VERSION 5.7 ;
BUSBITCHARS "[]" ;
DIVIDERCHAR "/" ;

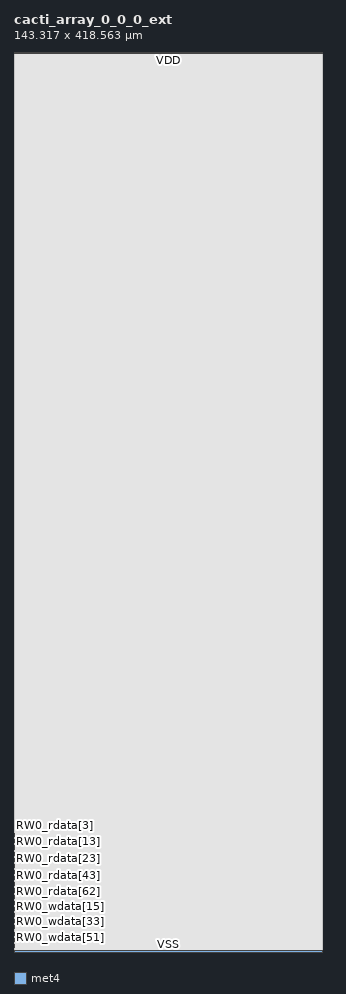
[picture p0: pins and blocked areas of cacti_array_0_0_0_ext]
MACRO cacti_array_0_0_0_ext
  CLASS BLOCK BLACKBOX ;
  ORIGIN 0 0 ;
  FOREIGN cacti_array_0_0_0_ext 0 0 ;
  SIZE 143.317 BY 418.563 ;
  SYMMETRY X Y ;

  PIN VDD
    DIRECTION INOUT ;
    USE POWER ;
    PORT
      LAYER met4 ;
        RECT 0.000 418.063 143.317 418.563 ;
    END
  END VDD
  PIN VSS
    DIRECTION INOUT ;
    USE GROUND ;
    PORT
      LAYER met4 ;
        RECT 0.000 0.000 143.317 0.500 ;
    END
  END VSS
  PIN RW0_clk
    DIRECTION INPUT ;
    USE CLOCK ;
    PORT
      LAYER met4 ;
        RECT 0.000 0.700 0.200 0.900 ;
    END
  END RW0_clk
  PIN RW0_en
    DIRECTION INPUT ;
    USE SIGNAL ;
    PORT
      LAYER met4 ;
        RECT 0.000 1.100 0.200 1.300 ;
    END
  END RW0_en
  PIN RW0_wmode
    DIRECTION INPUT ;
    USE SIGNAL ;
    PORT
      LAYER met4 ;
        RECT 0.000 1.500 0.200 1.700 ;
    END
  END RW0_wmode
  PIN RW0_addr[8]
    DIRECTION INPUT ;
    USE SIGNAL ;
    PORT
      LAYER met4 ;
        RECT 0.000 1.900 0.200 2.100 ;
    END
  END RW0_addr[8]
  PIN RW0_addr[7]
    DIRECTION INPUT ;
    USE SIGNAL ;
    PORT
      LAYER met4 ;
        RECT 0.000 2.300 0.200 2.500 ;
    END
  END RW0_addr[7]
  PIN RW0_addr[6]
    DIRECTION INPUT ;
    USE SIGNAL ;
    PORT
      LAYER met4 ;
        RECT 0.000 2.700 0.200 2.900 ;
    END
  END RW0_addr[6]
  PIN RW0_addr[5]
    DIRECTION INPUT ;
    USE SIGNAL ;
    PORT
      LAYER met4 ;
        RECT 0.000 3.100 0.200 3.300 ;
    END
  END RW0_addr[5]
  PIN RW0_addr[4]
    DIRECTION INPUT ;
    USE SIGNAL ;
    PORT
      LAYER met4 ;
        RECT 0.000 3.500 0.200 3.700 ;
    END
  END RW0_addr[4]
  PIN RW0_addr[3]
    DIRECTION INPUT ;
    USE SIGNAL ;
    PORT
      LAYER met4 ;
        RECT 0.000 3.900 0.200 4.100 ;
    END
  END RW0_addr[3]
  PIN RW0_addr[2]
    DIRECTION INPUT ;
    USE SIGNAL ;
    PORT
      LAYER met4 ;
        RECT 0.000 4.300 0.200 4.500 ;
    END
  END RW0_addr[2]
  PIN RW0_addr[1]
    DIRECTION INPUT ;
    USE SIGNAL ;
    PORT
      LAYER met4 ;
        RECT 0.000 4.700 0.200 4.900 ;
    END
  END RW0_addr[1]
  PIN RW0_addr[0]
    DIRECTION INPUT ;
    USE SIGNAL ;
    PORT
      LAYER met4 ;
        RECT 0.000 5.100 0.200 5.300 ;
    END
  END RW0_addr[0]
  PIN RW0_wdata[63]
    DIRECTION INPUT ;
    USE SIGNAL ;
    PORT
      LAYER met4 ;
        RECT 0.000 5.500 0.200 5.700 ;
    END
  END RW0_wdata[63]
  PIN RW0_wdata[62]
    DIRECTION INPUT ;
    USE SIGNAL ;
    PORT
      LAYER met4 ;
        RECT 0.000 5.900 0.200 6.100 ;
    END
  END RW0_wdata[62]
  PIN RW0_wdata[61]
    DIRECTION INPUT ;
    USE SIGNAL ;
    PORT
      LAYER met4 ;
        RECT 0.000 6.300 0.200 6.500 ;
    END
  END RW0_wdata[61]
  PIN RW0_wdata[60]
    DIRECTION INPUT ;
    USE SIGNAL ;
    PORT
      LAYER met4 ;
        RECT 0.000 6.700 0.200 6.900 ;
    END
  END RW0_wdata[60]
  PIN RW0_wdata[59]
    DIRECTION INPUT ;
    USE SIGNAL ;
    PORT
      LAYER met4 ;
        RECT 0.000 7.100 0.200 7.300 ;
    END
  END RW0_wdata[59]
  PIN RW0_wdata[58]
    DIRECTION INPUT ;
    USE SIGNAL ;
    PORT
      LAYER met4 ;
        RECT 0.000 7.500 0.200 7.700 ;
    END
  END RW0_wdata[58]
  PIN RW0_wdata[57]
    DIRECTION INPUT ;
    USE SIGNAL ;
    PORT
      LAYER met4 ;
        RECT 0.000 7.900 0.200 8.100 ;
    END
  END RW0_wdata[57]
  PIN RW0_wdata[56]
    DIRECTION INPUT ;
    USE SIGNAL ;
    PORT
      LAYER met4 ;
        RECT 0.000 8.300 0.200 8.500 ;
    END
  END RW0_wdata[56]
  PIN RW0_wdata[55]
    DIRECTION INPUT ;
    USE SIGNAL ;
    PORT
      LAYER met4 ;
        RECT 0.000 8.700 0.200 8.900 ;
    END
  END RW0_wdata[55]
  PIN RW0_wdata[54]
    DIRECTION INPUT ;
    USE SIGNAL ;
    PORT
      LAYER met4 ;
        RECT 0.000 9.100 0.200 9.300 ;
    END
  END RW0_wdata[54]
  PIN RW0_wdata[53]
    DIRECTION INPUT ;
    USE SIGNAL ;
    PORT
      LAYER met4 ;
        RECT 0.000 9.500 0.200 9.700 ;
    END
  END RW0_wdata[53]
  PIN RW0_wdata[52]
    DIRECTION INPUT ;
    USE SIGNAL ;
    PORT
      LAYER met4 ;
        RECT 0.000 9.900 0.200 10.100 ;
    END
  END RW0_wdata[52]
  PIN RW0_wdata[51]
    DIRECTION INPUT ;
    USE SIGNAL ;
    PORT
      LAYER met4 ;
        RECT 0.000 10.300 0.200 10.500 ;
    END
  END RW0_wdata[51]
  PIN RW0_wdata[50]
    DIRECTION INPUT ;
    USE SIGNAL ;
    PORT
      LAYER met4 ;
        RECT 0.000 10.700 0.200 10.900 ;
    END
  END RW0_wdata[50]
  PIN RW0_wdata[49]
    DIRECTION INPUT ;
    USE SIGNAL ;
    PORT
      LAYER met4 ;
        RECT 0.000 11.100 0.200 11.300 ;
    END
  END RW0_wdata[49]
  PIN RW0_wdata[48]
    DIRECTION INPUT ;
    USE SIGNAL ;
    PORT
      LAYER met4 ;
        RECT 0.000 11.500 0.200 11.700 ;
    END
  END RW0_wdata[48]
  PIN RW0_wdata[47]
    DIRECTION INPUT ;
    USE SIGNAL ;
    PORT
      LAYER met4 ;
        RECT 0.000 11.900 0.200 12.100 ;
    END
  END RW0_wdata[47]
  PIN RW0_wdata[46]
    DIRECTION INPUT ;
    USE SIGNAL ;
    PORT
      LAYER met4 ;
        RECT 0.000 12.300 0.200 12.500 ;
    END
  END RW0_wdata[46]
  PIN RW0_wdata[45]
    DIRECTION INPUT ;
    USE SIGNAL ;
    PORT
      LAYER met4 ;
        RECT 0.000 12.700 0.200 12.900 ;
    END
  END RW0_wdata[45]
  PIN RW0_wdata[44]
    DIRECTION INPUT ;
    USE SIGNAL ;
    PORT
      LAYER met4 ;
        RECT 0.000 13.100 0.200 13.300 ;
    END
  END RW0_wdata[44]
  PIN RW0_wdata[43]
    DIRECTION INPUT ;
    USE SIGNAL ;
    PORT
      LAYER met4 ;
        RECT 0.000 13.500 0.200 13.700 ;
    END
  END RW0_wdata[43]
  PIN RW0_wdata[42]
    DIRECTION INPUT ;
    USE SIGNAL ;
    PORT
      LAYER met4 ;
        RECT 0.000 13.900 0.200 14.100 ;
    END
  END RW0_wdata[42]
  PIN RW0_wdata[41]
    DIRECTION INPUT ;
    USE SIGNAL ;
    PORT
      LAYER met4 ;
        RECT 0.000 14.300 0.200 14.500 ;
    END
  END RW0_wdata[41]
  PIN RW0_wdata[40]
    DIRECTION INPUT ;
    USE SIGNAL ;
    PORT
      LAYER met4 ;
        RECT 0.000 14.700 0.200 14.900 ;
    END
  END RW0_wdata[40]
  PIN RW0_wdata[39]
    DIRECTION INPUT ;
    USE SIGNAL ;
    PORT
      LAYER met4 ;
        RECT 0.000 15.100 0.200 15.300 ;
    END
  END RW0_wdata[39]
  PIN RW0_wdata[38]
    DIRECTION INPUT ;
    USE SIGNAL ;
    PORT
      LAYER met4 ;
        RECT 0.000 15.500 0.200 15.700 ;
    END
  END RW0_wdata[38]
  PIN RW0_wdata[37]
    DIRECTION INPUT ;
    USE SIGNAL ;
    PORT
      LAYER met4 ;
        RECT 0.000 15.900 0.200 16.100 ;
    END
  END RW0_wdata[37]
  PIN RW0_wdata[36]
    DIRECTION INPUT ;
    USE SIGNAL ;
    PORT
      LAYER met4 ;
        RECT 0.000 16.300 0.200 16.500 ;
    END
  END RW0_wdata[36]
  PIN RW0_wdata[35]
    DIRECTION INPUT ;
    USE SIGNAL ;
    PORT
      LAYER met4 ;
        RECT 0.000 16.700 0.200 16.900 ;
    END
  END RW0_wdata[35]
  PIN RW0_wdata[34]
    DIRECTION INPUT ;
    USE SIGNAL ;
    PORT
      LAYER met4 ;
        RECT 0.000 17.100 0.200 17.300 ;
    END
  END RW0_wdata[34]
  PIN RW0_wdata[33]
    DIRECTION INPUT ;
    USE SIGNAL ;
    PORT
      LAYER met4 ;
        RECT 0.000 17.500 0.200 17.700 ;
    END
  END RW0_wdata[33]
  PIN RW0_wdata[32]
    DIRECTION INPUT ;
    USE SIGNAL ;
    PORT
      LAYER met4 ;
        RECT 0.000 17.900 0.200 18.100 ;
    END
  END RW0_wdata[32]
  PIN RW0_wdata[31]
    DIRECTION INPUT ;
    USE SIGNAL ;
    PORT
      LAYER met4 ;
        RECT 0.000 18.300 0.200 18.500 ;
    END
  END RW0_wdata[31]
  PIN RW0_wdata[30]
    DIRECTION INPUT ;
    USE SIGNAL ;
    PORT
      LAYER met4 ;
        RECT 0.000 18.700 0.200 18.900 ;
    END
  END RW0_wdata[30]
  PIN RW0_wdata[29]
    DIRECTION INPUT ;
    USE SIGNAL ;
    PORT
      LAYER met4 ;
        RECT 0.000 19.100 0.200 19.300 ;
    END
  END RW0_wdata[29]
  PIN RW0_wdata[28]
    DIRECTION INPUT ;
    USE SIGNAL ;
    PORT
      LAYER met4 ;
        RECT 0.000 19.500 0.200 19.700 ;
    END
  END RW0_wdata[28]
  PIN RW0_wdata[27]
    DIRECTION INPUT ;
    USE SIGNAL ;
    PORT
      LAYER met4 ;
        RECT 0.000 19.900 0.200 20.100 ;
    END
  END RW0_wdata[27]
  PIN RW0_wdata[26]
    DIRECTION INPUT ;
    USE SIGNAL ;
    PORT
      LAYER met4 ;
        RECT 0.000 20.300 0.200 20.500 ;
    END
  END RW0_wdata[26]
  PIN RW0_wdata[25]
    DIRECTION INPUT ;
    USE SIGNAL ;
    PORT
      LAYER met4 ;
        RECT 0.000 20.700 0.200 20.900 ;
    END
  END RW0_wdata[25]
  PIN RW0_wdata[24]
    DIRECTION INPUT ;
    USE SIGNAL ;
    PORT
      LAYER met4 ;
        RECT 0.000 21.100 0.200 21.300 ;
    END
  END RW0_wdata[24]
  PIN RW0_wdata[23]
    DIRECTION INPUT ;
    USE SIGNAL ;
    PORT
      LAYER met4 ;
        RECT 0.000 21.500 0.200 21.700 ;
    END
  END RW0_wdata[23]
  PIN RW0_wdata[22]
    DIRECTION INPUT ;
    USE SIGNAL ;
    PORT
      LAYER met4 ;
        RECT 0.000 21.900 0.200 22.100 ;
    END
  END RW0_wdata[22]
  PIN RW0_wdata[21]
    DIRECTION INPUT ;
    USE SIGNAL ;
    PORT
      LAYER met4 ;
        RECT 0.000 22.300 0.200 22.500 ;
    END
  END RW0_wdata[21]
  PIN RW0_wdata[20]
    DIRECTION INPUT ;
    USE SIGNAL ;
    PORT
      LAYER met4 ;
        RECT 0.000 22.700 0.200 22.900 ;
    END
  END RW0_wdata[20]
  PIN RW0_wdata[19]
    DIRECTION INPUT ;
    USE SIGNAL ;
    PORT
      LAYER met4 ;
        RECT 0.000 23.100 0.200 23.300 ;
    END
  END RW0_wdata[19]
  PIN RW0_wdata[18]
    DIRECTION INPUT ;
    USE SIGNAL ;
    PORT
      LAYER met4 ;
        RECT 0.000 23.500 0.200 23.700 ;
    END
  END RW0_wdata[18]
  PIN RW0_wdata[17]
    DIRECTION INPUT ;
    USE SIGNAL ;
    PORT
      LAYER met4 ;
        RECT 0.000 23.900 0.200 24.100 ;
    END
  END RW0_wdata[17]
  PIN RW0_wdata[16]
    DIRECTION INPUT ;
    USE SIGNAL ;
    PORT
      LAYER met4 ;
        RECT 0.000 24.300 0.200 24.500 ;
    END
  END RW0_wdata[16]
  PIN RW0_wdata[15]
    DIRECTION INPUT ;
    USE SIGNAL ;
    PORT
      LAYER met4 ;
        RECT 0.000 24.700 0.200 24.900 ;
    END
  END RW0_wdata[15]
  PIN RW0_wdata[14]
    DIRECTION INPUT ;
    USE SIGNAL ;
    PORT
      LAYER met4 ;
        RECT 0.000 25.100 0.200 25.300 ;
    END
  END RW0_wdata[14]
  PIN RW0_wdata[13]
    DIRECTION INPUT ;
    USE SIGNAL ;
    PORT
      LAYER met4 ;
        RECT 0.000 25.500 0.200 25.700 ;
    END
  END RW0_wdata[13]
  PIN RW0_wdata[12]
    DIRECTION INPUT ;
    USE SIGNAL ;
    PORT
      LAYER met4 ;
        RECT 0.000 25.900 0.200 26.100 ;
    END
  END RW0_wdata[12]
  PIN RW0_wdata[11]
    DIRECTION INPUT ;
    USE SIGNAL ;
    PORT
      LAYER met4 ;
        RECT 0.000 26.300 0.200 26.500 ;
    END
  END RW0_wdata[11]
  PIN RW0_wdata[10]
    DIRECTION INPUT ;
    USE SIGNAL ;
    PORT
      LAYER met4 ;
        RECT 0.000 26.700 0.200 26.900 ;
    END
  END RW0_wdata[10]
  PIN RW0_wdata[9]
    DIRECTION INPUT ;
    USE SIGNAL ;
    PORT
      LAYER met4 ;
        RECT 0.000 27.100 0.200 27.300 ;
    END
  END RW0_wdata[9]
  PIN RW0_wdata[8]
    DIRECTION INPUT ;
    USE SIGNAL ;
    PORT
      LAYER met4 ;
        RECT 0.000 27.500 0.200 27.700 ;
    END
  END RW0_wdata[8]
  PIN RW0_wdata[7]
    DIRECTION INPUT ;
    USE SIGNAL ;
    PORT
      LAYER met4 ;
        RECT 0.000 27.900 0.200 28.100 ;
    END
  END RW0_wdata[7]
  PIN RW0_wdata[6]
    DIRECTION INPUT ;
    USE SIGNAL ;
    PORT
      LAYER met4 ;
        RECT 0.000 28.300 0.200 28.500 ;
    END
  END RW0_wdata[6]
  PIN RW0_wdata[5]
    DIRECTION INPUT ;
    USE SIGNAL ;
    PORT
      LAYER met4 ;
        RECT 0.000 28.700 0.200 28.900 ;
    END
  END RW0_wdata[5]
  PIN RW0_wdata[4]
    DIRECTION INPUT ;
    USE SIGNAL ;
    PORT
      LAYER met4 ;
        RECT 0.000 29.100 0.200 29.300 ;
    END
  END RW0_wdata[4]
  PIN RW0_wdata[3]
    DIRECTION INPUT ;
    USE SIGNAL ;
    PORT
      LAYER met4 ;
        RECT 0.000 29.500 0.200 29.700 ;
    END
  END RW0_wdata[3]
  PIN RW0_wdata[2]
    DIRECTION INPUT ;
    USE SIGNAL ;
    PORT
      LAYER met4 ;
        RECT 0.000 29.900 0.200 30.100 ;
    END
  END RW0_wdata[2]
  PIN RW0_wdata[1]
    DIRECTION INPUT ;
    USE SIGNAL ;
    PORT
      LAYER met4 ;
        RECT 0.000 30.300 0.200 30.500 ;
    END
  END RW0_wdata[1]
  PIN RW0_wdata[0]
    DIRECTION INPUT ;
    USE SIGNAL ;
    PORT
      LAYER met4 ;
        RECT 0.000 30.700 0.200 30.900 ;
    END
  END RW0_wdata[0]
  PIN RW0_rdata[63]
    DIRECTION OUTPUT ;
    USE SIGNAL ;
    PORT
      LAYER met4 ;
        RECT 0.000 31.100 0.200 31.300 ;
    END
  END RW0_rdata[63]
  PIN RW0_rdata[62]
    DIRECTION OUTPUT ;
    USE SIGNAL ;
    PORT
      LAYER met4 ;
        RECT 0.000 31.500 0.200 31.700 ;
    END
  END RW0_rdata[62]
  PIN RW0_rdata[61]
    DIRECTION OUTPUT ;
    USE SIGNAL ;
    PORT
      LAYER met4 ;
        RECT 0.000 31.900 0.200 32.100 ;
    END
  END RW0_rdata[61]
  PIN RW0_rdata[60]
    DIRECTION OUTPUT ;
    USE SIGNAL ;
    PORT
      LAYER met4 ;
        RECT 0.000 32.300 0.200 32.500 ;
    END
  END RW0_rdata[60]
  PIN RW0_rdata[59]
    DIRECTION OUTPUT ;
    USE SIGNAL ;
    PORT
      LAYER met4 ;
        RECT 0.000 32.700 0.200 32.900 ;
    END
  END RW0_rdata[59]
  PIN RW0_rdata[58]
    DIRECTION OUTPUT ;
    USE SIGNAL ;
    PORT
      LAYER met4 ;
        RECT 0.000 33.100 0.200 33.300 ;
    END
  END RW0_rdata[58]
  PIN RW0_rdata[57]
    DIRECTION OUTPUT ;
    USE SIGNAL ;
    PORT
      LAYER met4 ;
        RECT 0.000 33.500 0.200 33.700 ;
    END
  END RW0_rdata[57]
  PIN RW0_rdata[56]
    DIRECTION OUTPUT ;
    USE SIGNAL ;
    PORT
      LAYER met4 ;
        RECT 0.000 33.900 0.200 34.100 ;
    END
  END RW0_rdata[56]
  PIN RW0_rdata[55]
    DIRECTION OUTPUT ;
    USE SIGNAL ;
    PORT
      LAYER met4 ;
        RECT 0.000 34.300 0.200 34.500 ;
    END
  END RW0_rdata[55]
  PIN RW0_rdata[54]
    DIRECTION OUTPUT ;
    USE SIGNAL ;
    PORT
      LAYER met4 ;
        RECT 0.000 34.700 0.200 34.900 ;
    END
  END RW0_rdata[54]
  PIN RW0_rdata[53]
    DIRECTION OUTPUT ;
    USE SIGNAL ;
    PORT
      LAYER met4 ;
        RECT 0.000 35.100 0.200 35.300 ;
    END
  END RW0_rdata[53]
  PIN RW0_rdata[52]
    DIRECTION OUTPUT ;
    USE SIGNAL ;
    PORT
      LAYER met4 ;
        RECT 0.000 35.500 0.200 35.700 ;
    END
  END RW0_rdata[52]
  PIN RW0_rdata[51]
    DIRECTION OUTPUT ;
    USE SIGNAL ;
    PORT
      LAYER met4 ;
        RECT 0.000 35.900 0.200 36.100 ;
    END
  END RW0_rdata[51]
  PIN RW0_rdata[50]
    DIRECTION OUTPUT ;
    USE SIGNAL ;
    PORT
      LAYER met4 ;
        RECT 0.000 36.300 0.200 36.500 ;
    END
  END RW0_rdata[50]
  PIN RW0_rdata[49]
    DIRECTION OUTPUT ;
    USE SIGNAL ;
    PORT
      LAYER met4 ;
        RECT 0.000 36.700 0.200 36.900 ;
    END
  END RW0_rdata[49]
  PIN RW0_rdata[48]
    DIRECTION OUTPUT ;
    USE SIGNAL ;
    PORT
      LAYER met4 ;
        RECT 0.000 37.100 0.200 37.300 ;
    END
  END RW0_rdata[48]
  PIN RW0_rdata[47]
    DIRECTION OUTPUT ;
    USE SIGNAL ;
    PORT
      LAYER met4 ;
        RECT 0.000 37.500 0.200 37.700 ;
    END
  END RW0_rdata[47]
  PIN RW0_rdata[46]
    DIRECTION OUTPUT ;
    USE SIGNAL ;
    PORT
      LAYER met4 ;
        RECT 0.000 37.900 0.200 38.100 ;
    END
  END RW0_rdata[46]
  PIN RW0_rdata[45]
    DIRECTION OUTPUT ;
    USE SIGNAL ;
    PORT
      LAYER met4 ;
        RECT 0.000 38.300 0.200 38.500 ;
    END
  END RW0_rdata[45]
  PIN RW0_rdata[44]
    DIRECTION OUTPUT ;
    USE SIGNAL ;
    PORT
      LAYER met4 ;
        RECT 0.000 38.700 0.200 38.900 ;
    END
  END RW0_rdata[44]
  PIN RW0_rdata[43]
    DIRECTION OUTPUT ;
    USE SIGNAL ;
    PORT
      LAYER met4 ;
        RECT 0.000 39.100 0.200 39.300 ;
    END
  END RW0_rdata[43]
  PIN RW0_rdata[42]
    DIRECTION OUTPUT ;
    USE SIGNAL ;
    PORT
      LAYER met4 ;
        RECT 0.000 39.500 0.200 39.700 ;
    END
  END RW0_rdata[42]
  PIN RW0_rdata[41]
    DIRECTION OUTPUT ;
    USE SIGNAL ;
    PORT
      LAYER met4 ;
        RECT 0.000 39.900 0.200 40.100 ;
    END
  END RW0_rdata[41]
  PIN RW0_rdata[40]
    DIRECTION OUTPUT ;
    USE SIGNAL ;
    PORT
      LAYER met4 ;
        RECT 0.000 40.300 0.200 40.500 ;
    END
  END RW0_rdata[40]
  PIN RW0_rdata[39]
    DIRECTION OUTPUT ;
    USE SIGNAL ;
    PORT
      LAYER met4 ;
        RECT 0.000 40.700 0.200 40.900 ;
    END
  END RW0_rdata[39]
  PIN RW0_rdata[38]
    DIRECTION OUTPUT ;
    USE SIGNAL ;
    PORT
      LAYER met4 ;
        RECT 0.000 41.100 0.200 41.300 ;
    END
  END RW0_rdata[38]
  PIN RW0_rdata[37]
    DIRECTION OUTPUT ;
    USE SIGNAL ;
    PORT
      LAYER met4 ;
        RECT 0.000 41.500 0.200 41.700 ;
    END
  END RW0_rdata[37]
  PIN RW0_rdata[36]
    DIRECTION OUTPUT ;
    USE SIGNAL ;
    PORT
      LAYER met4 ;
        RECT 0.000 41.900 0.200 42.100 ;
    END
  END RW0_rdata[36]
  PIN RW0_rdata[35]
    DIRECTION OUTPUT ;
    USE SIGNAL ;
    PORT
      LAYER met4 ;
        RECT 0.000 42.300 0.200 42.500 ;
    END
  END RW0_rdata[35]
  PIN RW0_rdata[34]
    DIRECTION OUTPUT ;
    USE SIGNAL ;
    PORT
      LAYER met4 ;
        RECT 0.000 42.700 0.200 42.900 ;
    END
  END RW0_rdata[34]
  PIN RW0_rdata[33]
    DIRECTION OUTPUT ;
    USE SIGNAL ;
    PORT
      LAYER met4 ;
        RECT 0.000 43.100 0.200 43.300 ;
    END
  END RW0_rdata[33]
  PIN RW0_rdata[32]
    DIRECTION OUTPUT ;
    USE SIGNAL ;
    PORT
      LAYER met4 ;
        RECT 0.000 43.500 0.200 43.700 ;
    END
  END RW0_rdata[32]
  PIN RW0_rdata[31]
    DIRECTION OUTPUT ;
    USE SIGNAL ;
    PORT
      LAYER met4 ;
        RECT 0.000 43.900 0.200 44.100 ;
    END
  END RW0_rdata[31]
  PIN RW0_rdata[30]
    DIRECTION OUTPUT ;
    USE SIGNAL ;
    PORT
      LAYER met4 ;
        RECT 0.000 44.300 0.200 44.500 ;
    END
  END RW0_rdata[30]
  PIN RW0_rdata[29]
    DIRECTION OUTPUT ;
    USE SIGNAL ;
    PORT
      LAYER met4 ;
        RECT 0.000 44.700 0.200 44.900 ;
    END
  END RW0_rdata[29]
  PIN RW0_rdata[28]
    DIRECTION OUTPUT ;
    USE SIGNAL ;
    PORT
      LAYER met4 ;
        RECT 0.000 45.100 0.200 45.300 ;
    END
  END RW0_rdata[28]
  PIN RW0_rdata[27]
    DIRECTION OUTPUT ;
    USE SIGNAL ;
    PORT
      LAYER met4 ;
        RECT 0.000 45.500 0.200 45.700 ;
    END
  END RW0_rdata[27]
  PIN RW0_rdata[26]
    DIRECTION OUTPUT ;
    USE SIGNAL ;
    PORT
      LAYER met4 ;
        RECT 0.000 45.900 0.200 46.100 ;
    END
  END RW0_rdata[26]
  PIN RW0_rdata[25]
    DIRECTION OUTPUT ;
    USE SIGNAL ;
    PORT
      LAYER met4 ;
        RECT 0.000 46.300 0.200 46.500 ;
    END
  END RW0_rdata[25]
  PIN RW0_rdata[24]
    DIRECTION OUTPUT ;
    USE SIGNAL ;
    PORT
      LAYER met4 ;
        RECT 0.000 46.700 0.200 46.900 ;
    END
  END RW0_rdata[24]
  PIN RW0_rdata[23]
    DIRECTION OUTPUT ;
    USE SIGNAL ;
    PORT
      LAYER met4 ;
        RECT 0.000 47.100 0.200 47.300 ;
    END
  END RW0_rdata[23]
  PIN RW0_rdata[22]
    DIRECTION OUTPUT ;
    USE SIGNAL ;
    PORT
      LAYER met4 ;
        RECT 0.000 47.500 0.200 47.700 ;
    END
  END RW0_rdata[22]
  PIN RW0_rdata[21]
    DIRECTION OUTPUT ;
    USE SIGNAL ;
    PORT
      LAYER met4 ;
        RECT 0.000 47.900 0.200 48.100 ;
    END
  END RW0_rdata[21]
  PIN RW0_rdata[20]
    DIRECTION OUTPUT ;
    USE SIGNAL ;
    PORT
      LAYER met4 ;
        RECT 0.000 48.300 0.200 48.500 ;
    END
  END RW0_rdata[20]
  PIN RW0_rdata[19]
    DIRECTION OUTPUT ;
    USE SIGNAL ;
    PORT
      LAYER met4 ;
        RECT 0.000 48.700 0.200 48.900 ;
    END
  END RW0_rdata[19]
  PIN RW0_rdata[18]
    DIRECTION OUTPUT ;
    USE SIGNAL ;
    PORT
      LAYER met4 ;
        RECT 0.000 49.100 0.200 49.300 ;
    END
  END RW0_rdata[18]
  PIN RW0_rdata[17]
    DIRECTION OUTPUT ;
    USE SIGNAL ;
    PORT
      LAYER met4 ;
        RECT 0.000 49.500 0.200 49.700 ;
    END
  END RW0_rdata[17]
  PIN RW0_rdata[16]
    DIRECTION OUTPUT ;
    USE SIGNAL ;
    PORT
      LAYER met4 ;
        RECT 0.000 49.900 0.200 50.100 ;
    END
  END RW0_rdata[16]
  PIN RW0_rdata[15]
    DIRECTION OUTPUT ;
    USE SIGNAL ;
    PORT
      LAYER met4 ;
        RECT 0.000 50.300 0.200 50.500 ;
    END
  END RW0_rdata[15]
  PIN RW0_rdata[14]
    DIRECTION OUTPUT ;
    USE SIGNAL ;
    PORT
      LAYER met4 ;
        RECT 0.000 50.700 0.200 50.900 ;
    END
  END RW0_rdata[14]
  PIN RW0_rdata[13]
    DIRECTION OUTPUT ;
    USE SIGNAL ;
    PORT
      LAYER met4 ;
        RECT 0.000 51.100 0.200 51.300 ;
    END
  END RW0_rdata[13]
  PIN RW0_rdata[12]
    DIRECTION OUTPUT ;
    USE SIGNAL ;
    PORT
      LAYER met4 ;
        RECT 0.000 51.500 0.200 51.700 ;
    END
  END RW0_rdata[12]
  PIN RW0_rdata[11]
    DIRECTION OUTPUT ;
    USE SIGNAL ;
    PORT
      LAYER met4 ;
        RECT 0.000 51.900 0.200 52.100 ;
    END
  END RW0_rdata[11]
  PIN RW0_rdata[10]
    DIRECTION OUTPUT ;
    USE SIGNAL ;
    PORT
      LAYER met4 ;
        RECT 0.000 52.300 0.200 52.500 ;
    END
  END RW0_rdata[10]
  PIN RW0_rdata[9]
    DIRECTION OUTPUT ;
    USE SIGNAL ;
    PORT
      LAYER met4 ;
        RECT 0.000 52.700 0.200 52.900 ;
    END
  END RW0_rdata[9]
  PIN RW0_rdata[8]
    DIRECTION OUTPUT ;
    USE SIGNAL ;
    PORT
      LAYER met4 ;
        RECT 0.000 53.100 0.200 53.300 ;
    END
  END RW0_rdata[8]
  PIN RW0_rdata[7]
    DIRECTION OUTPUT ;
    USE SIGNAL ;
    PORT
      LAYER met4 ;
        RECT 0.000 53.500 0.200 53.700 ;
    END
  END RW0_rdata[7]
  PIN RW0_rdata[6]
    DIRECTION OUTPUT ;
    USE SIGNAL ;
    PORT
      LAYER met4 ;
        RECT 0.000 53.900 0.200 54.100 ;
    END
  END RW0_rdata[6]
  PIN RW0_rdata[5]
    DIRECTION OUTPUT ;
    USE SIGNAL ;
    PORT
      LAYER met4 ;
        RECT 0.000 54.300 0.200 54.500 ;
    END
  END RW0_rdata[5]
  PIN RW0_rdata[4]
    DIRECTION OUTPUT ;
    USE SIGNAL ;
    PORT
      LAYER met4 ;
        RECT 0.000 54.700 0.200 54.900 ;
    END
  END RW0_rdata[4]
  PIN RW0_rdata[3]
    DIRECTION OUTPUT ;
    USE SIGNAL ;
    PORT
      LAYER met4 ;
        RECT 0.000 55.100 0.200 55.300 ;
    END
  END RW0_rdata[3]
  PIN RW0_rdata[2]
    DIRECTION OUTPUT ;
    USE SIGNAL ;
    PORT
      LAYER met4 ;
        RECT 0.000 55.500 0.200 55.700 ;
    END
  END RW0_rdata[2]
  PIN RW0_rdata[1]
    DIRECTION OUTPUT ;
    USE SIGNAL ;
    PORT
      LAYER met4 ;
        RECT 0.000 55.900 0.200 56.100 ;
    END
  END RW0_rdata[1]
  PIN RW0_rdata[0]
    DIRECTION OUTPUT ;
    USE SIGNAL ;
    PORT
      LAYER met4 ;
        RECT 0.000 56.300 0.200 56.500 ;
    END
  END RW0_rdata[0]
  OBS
    LAYER met1 ;
      RECT 0.000 0.000 143.317 418.563 ;
    LAYER met2 ;
      RECT 0.000 0.000 143.317 418.563 ;
    LAYER met3 ;
      RECT 0.000 0.000 143.317 418.563 ;
  END
END cacti_array_0_0_0_ext

END LIBRARY
